VERSION 5.7 ;
  NOWIREEXTENSIONATPIN ON ;
  DIVIDERCHAR "/" ;
  BUSBITCHARS "[]" ;
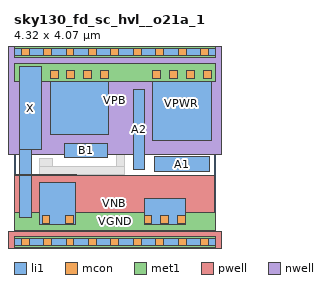
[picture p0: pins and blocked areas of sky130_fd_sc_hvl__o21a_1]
MACRO sky130_fd_sc_hvl__o21a_1
  CLASS BLOCK ;
  FOREIGN sky130_fd_sc_hvl__o21a_1 ;
  ORIGIN 0.000 0.000 ;
  SIZE 4.320 BY 4.070 ;
  PIN A1
    ANTENNAGATEAREA 1.125000 ;
    PORT
      LAYER li1 ;
        RECT 3.005 1.505 4.195 1.835 ;
    END
  END A1
  PIN A2
    ANTENNAGATEAREA 1.125000 ;
    PORT
      LAYER li1 ;
        RECT 2.555 1.550 2.785 3.260 ;
    END
  END A2
  PIN B1
    ANTENNAGATEAREA 1.125000 ;
    PORT
      LAYER li1 ;
        RECT 1.085 1.805 2.000 2.120 ;
    END
  END B1
  PIN VGND
    USE GROUND ;
    PORT
      LAYER li1 ;
        RECT 0.550 0.365 1.315 1.275 ;
        RECT 2.785 0.365 3.675 0.925 ;
      LAYER mcon ;
        RECT 0.600 0.395 0.770 0.565 ;
        RECT 1.105 0.395 1.275 0.565 ;
        RECT 2.785 0.395 2.955 0.565 ;
        RECT 3.145 0.395 3.315 0.565 ;
        RECT 3.505 0.395 3.675 0.565 ;
      LAYER met1 ;
        RECT 0.000 0.255 4.320 0.625 ;
    END
  END VGND
  PIN VNB
    ANTENNADIFFAREA 0.734400 ;
    PORT
      LAYER pwell ;
        RECT 0.020 1.415 1.330 1.445 ;
        RECT 0.020 0.215 4.295 1.415 ;
        RECT -0.130 -0.215 4.450 0.215 ;
      LAYER li1 ;
        RECT 0.000 -0.085 4.320 0.085 ;
      LAYER mcon ;
        RECT 0.155 -0.085 0.325 0.085 ;
        RECT 0.635 -0.085 0.805 0.085 ;
        RECT 1.115 -0.085 1.285 0.085 ;
        RECT 1.595 -0.085 1.765 0.085 ;
        RECT 2.075 -0.085 2.245 0.085 ;
        RECT 2.555 -0.085 2.725 0.085 ;
        RECT 3.035 -0.085 3.205 0.085 ;
        RECT 3.515 -0.085 3.685 0.085 ;
        RECT 3.995 -0.085 4.165 0.085 ;
      LAYER met1 ;
        RECT 0.000 -0.115 4.320 0.115 ;
    END
  END VNB
  PIN VPB
    ANTENNADIFFAREA 0.734400 ;
    PORT
      LAYER nwell ;
        RECT -0.330 1.885 4.650 4.485 ;
      LAYER li1 ;
        RECT 0.000 3.985 4.320 4.155 ;
      LAYER mcon ;
        RECT 0.155 3.985 0.325 4.155 ;
        RECT 0.635 3.985 0.805 4.155 ;
        RECT 1.115 3.985 1.285 4.155 ;
        RECT 1.595 3.985 1.765 4.155 ;
        RECT 2.075 3.985 2.245 4.155 ;
        RECT 2.555 3.985 2.725 4.155 ;
        RECT 3.035 3.985 3.205 4.155 ;
        RECT 3.515 3.985 3.685 4.155 ;
        RECT 3.995 3.985 4.165 4.155 ;
      LAYER met1 ;
        RECT 0.000 3.955 4.320 4.185 ;
    END
  END VPB
  PIN VPWR
    USE POWER ;
    PORT
      LAYER li1 ;
        RECT 0.775 2.300 2.025 3.755 ;
        RECT 2.965 2.175 4.230 3.755 ;
      LAYER mcon ;
        RECT 0.775 3.505 0.945 3.675 ;
        RECT 1.135 3.505 1.305 3.675 ;
        RECT 1.495 3.505 1.665 3.675 ;
        RECT 1.855 3.505 2.025 3.675 ;
        RECT 2.970 3.505 3.140 3.675 ;
        RECT 3.330 3.505 3.500 3.675 ;
        RECT 3.690 3.505 3.860 3.675 ;
        RECT 4.050 3.505 4.220 3.675 ;
      LAYER met1 ;
        RECT 0.000 3.445 4.320 3.815 ;
    END
  END VPWR
  PIN X
    ANTENNADIFFAREA 0.626250 ;
    PORT
      LAYER li1 ;
        RECT 0.125 1.975 0.595 3.755 ;
        RECT 0.125 0.525 0.380 1.975 ;
    END
  END X
  OBS
      LAYER li1 ;
        RECT 0.550 1.625 0.835 1.795 ;
        RECT 2.205 1.625 2.375 3.755 ;
        RECT 0.550 1.455 2.375 1.625 ;
        RECT 1.495 0.495 1.825 1.455 ;
        RECT 3.855 1.275 4.185 1.325 ;
        RECT 2.275 1.105 4.185 1.275 ;
        RECT 2.275 0.495 2.605 1.105 ;
        RECT 3.855 0.495 4.185 1.105 ;
  END
END sky130_fd_sc_hvl__o21a_1
END LIBRARY

